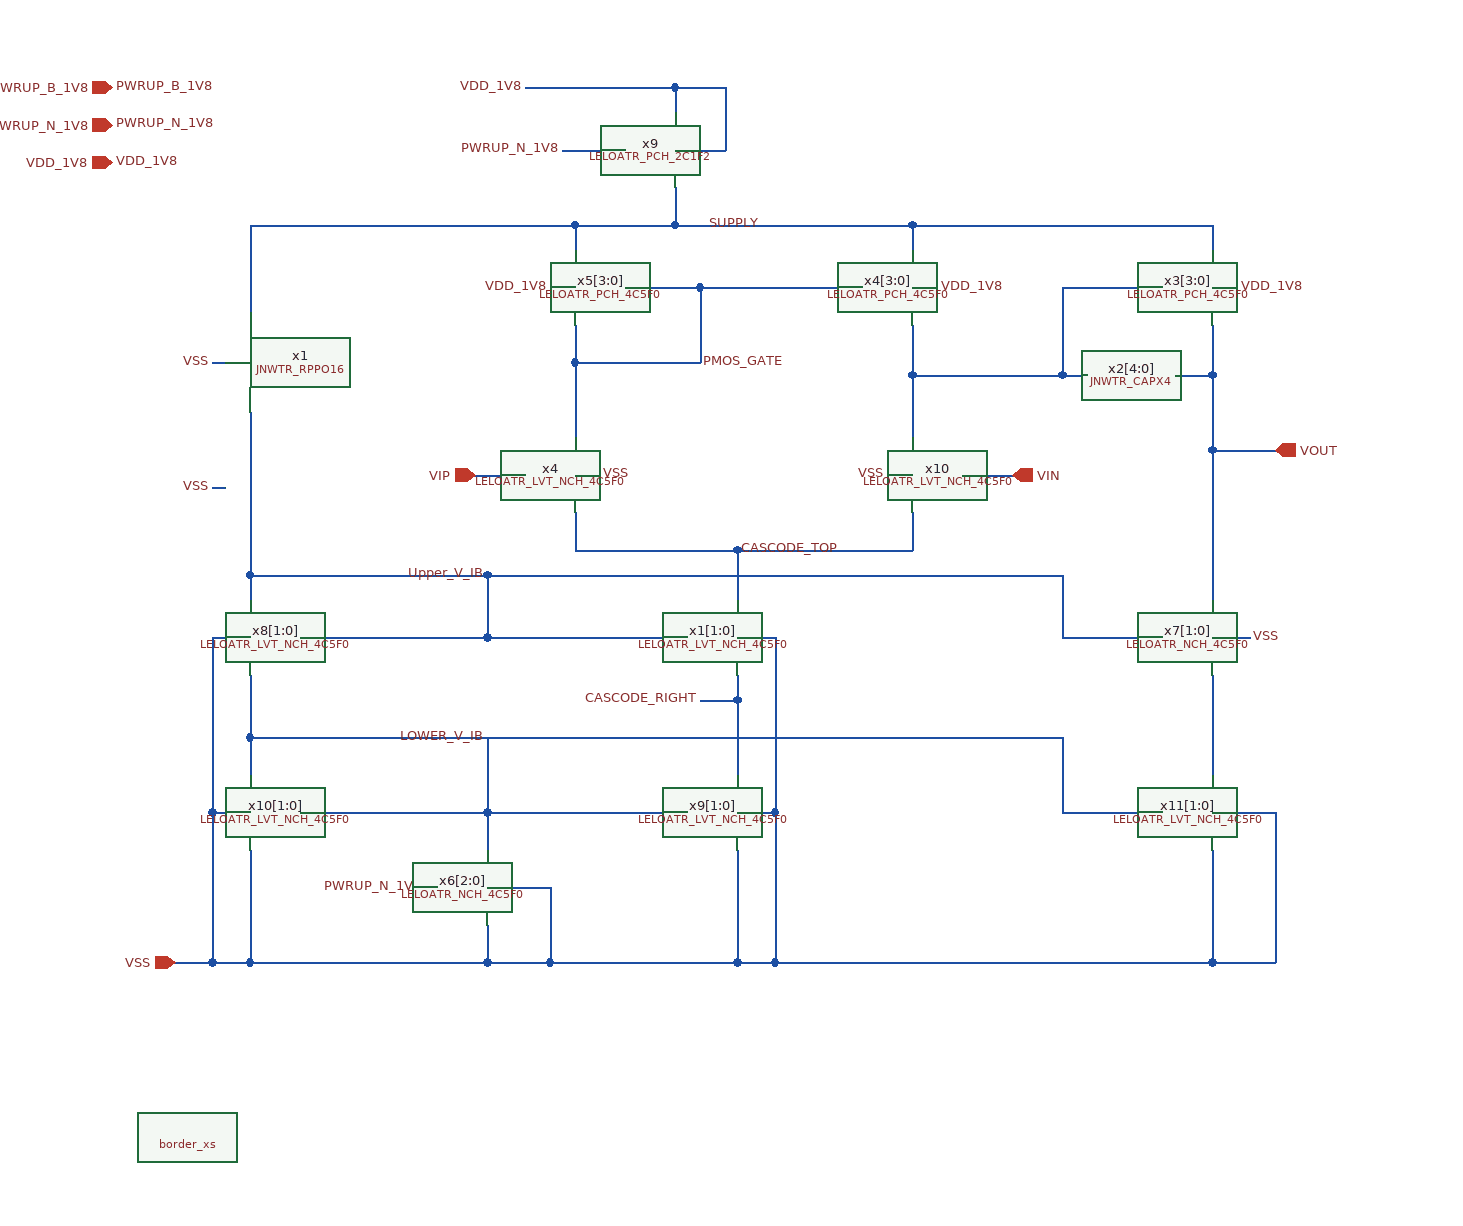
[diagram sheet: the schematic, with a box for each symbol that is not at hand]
v {xschem version=3.4.7 file_version=1.2}
G {}
K {}
V {}
S {}
E {}
N -510 -470 -450 -470 {lab=PMOS_GATE}
N -550 -410 -550 -350 {lab=PMOS_GATE}
N -280 -400 -280 -350 {lab=#net1}
N -550 -410 -450 -410 {lab=PMOS_GATE}
N -240 -320 -200 -320 {lab=VIN}
N -550 -290 -550 -260 {lab=CASCODE_TOP}
N -280 -290 -280 -260 {lab=CASCODE_TOP}
N -450 -470 -320 -470 {lab=PMOS_GATE}
N -450 -470 -450 -410 {lab=PMOS_GATE}
N -420 -260 -280 -260 {lab=CASCODE_TOP}
N -420 -260 -420 -220 {lab=CASCODE_TOP}
N -620 -190 -460 -190 {lab=Upper_V_IB}
N -840 -190 -810 -190 {lab=VSS}
N -420 -190 -390 -190 {lab=VSS}
N -280 -520 -280 -500 {lab=SUPPLY}
N -470 -520 -280 -520 {lab=SUPPLY}
N -550 -520 -550 -500 {lab=SUPPLY}
N -280 -470 -260 -470 {lab=VDD_1V8}
N -560 -580 -510 -580 {lab=PWRUP_N_1V8}
N -590 -630 -470 -630 {lab=VDD_1V8}
N -470 -630 -470 -610 {lab=VDD_1V8}
N -470 -550 -470 -520 {lab=SUPPLY}
N -470 -580 -430 -580 {lab=VDD_1V8}
N -430 -630 -430 -580 {lab=VDD_1V8}
N -470 -630 -430 -630 {lab=VDD_1V8}
N -420 70 -390 70 {lab=VSS}
N -570 -470 -550 -470 {lab=VDD_1V8}
N -810 -240 -620 -240 {lab=Upper_V_IB}
N -550 -320 -530 -320 {lab=VSS}
N -300 -320 -280 -320 {lab=VSS}
N -280 -520 -40 -520 {lab=SUPPLY}
N -40 -520 -40 -500 {lab=SUPPLY}
N -40 -470 -20 -470 {lab=VDD_1V8}
N -40 -190 -10 -190 {lab=VSS}
N -40 -340 10 -340 {lab=VOUT}
N -630 -320 -590 -320 {lab=VIP}
N -810 -270 -810 -240 {lab=Upper_V_IB}
N -810 -240 -810 -220 {lab=Upper_V_IB}
N -840 -310 -830 -310 {lab=VSS}
N -840 -410 -830 -410 {lab=VSS}
N -810 -370 -810 -350 {lab=Upper_V_IB}
N -810 -520 -550 -520 {lab=SUPPLY}
N -810 -520 -810 -450 {lab=SUPPLY}
N -40 -440 -40 -400 {lab=VOUT}
N -40 -340 -40 -220 {lab=VOUT}
N -620 40 -620 70 {lab=VSS}
N -390 -190 -390 -80 {lab=VSS}
N -390 70 -40 70 {lab=VSS}
N -160 -400 -140 -400 {lab=#net1}
N -70 -400 -40 -400 {lab=VOUT}
N -160 -470 -160 -400 {lab=#net1}
N -160 -470 -80 -470 {lab=#net1}
N -280 -400 -160 -400 {lab=#net1}
N -550 -260 -420 -260 {lab=CASCODE_TOP}
N -770 -190 -620 -190 {lab=Upper_V_IB}
N -620 -240 -620 -190 {lab=Upper_V_IB}
N -570 10 -570 70 {lab=VSS}
N -620 -50 -460 -50 {lab=LOWER_V_IB}
N -840 -50 -840 70 {lab=VSS}
N -390 -50 -390 70 {lab=VSS}
N -620 -50 -620 -20 {lab=LOWER_V_IB}
N -620 10 -570 10 {lab=VSS}
N -840 -50 -810 -50 {lab=VSS}
N -40 -50 -10 -50 {lab=VSS}
N -550 -440 -550 -410 {lab=PMOS_GATE}
N -570 70 -420 70 {lab=VSS}
N -550 -520 -470 -520 {lab=SUPPLY}
N -40 -400 -40 -340 {lab=VOUT}
N -810 70 -620 70 {lab=VSS}
N -840 70 -810 70 {lab=VSS}
N -870 70 -840 70 {lab=VSS}
N -280 -440 -280 -400 {lab=#net1}
N -620 70 -570 70 {lab=VSS}
N -810 -160 -810 -140 {lab=LOWER_V_IB}
N -770 -50 -620 -50 {lab=LOWER_V_IB}
N -840 -190 -840 -80 {lab=VSS}
N -40 -160 -40 -130 {lab=#net2}
N -420 -20 -420 70 {lab=VSS}
N -810 -20 -810 70 {lab=VSS}
N -810 -110 -810 -80 {lab=LOWER_V_IB}
N -420 -50 -390 -50 {lab=VSS}
N -40 70 10 70 {lab=VSS}
N 10 -50 10 70 {lab=VSS}
N -10 -50 10 -50 {lab=VSS}
N -810 -110 -740 -110 {lab=LOWER_V_IB}
N -160 -50 -80 -50 {lab=LOWER_V_IB}
N -160 -110 -160 -50 {lab=LOWER_V_IB}
N -160 -190 -80 -190 {lab=Upper_V_IB}
N -160 -240 -160 -190 {lab=Upper_V_IB}
N -620 -240 -160 -240 {lab=Upper_V_IB}
N -740 -110 -530 -110 {lab=LOWER_V_IB}
N -40 -100 -40 -80 {lab=#net2}
N -40 -20 -40 70 {lab=VSS}
N -810 -350 -810 -270 {lab=Upper_V_IB}
N -620 -110 -620 -50 {lab=LOWER_V_IB}
N -450 -140 -430 -140 {lab=CASCODE_RIGHT}
N -670 10 -660 10 {lab=PWRUP_N_1V8}
N -40 -130 -40 -100 {lab=#net2}
N -390 -80 -390 -50 {lab=VSS}
N -430 -140 -420 -140 {lab=CASCODE_RIGHT}
N -810 -140 -810 -110 {lab=LOWER_V_IB}
N -840 -80 -840 -50 {lab=VSS}
N -530 -110 -160 -110 {lab=LOWER_V_IB}
N -420 -160 -420 -140 {lab=CASCODE_RIGHT}
N -420 -140 -420 -80 {lab=CASCODE_RIGHT}
C {cborder/border_xs.sym} -860 210 0 0 {
user="Group 2"
company=""}
C {devices/ipin.sym} -870 70 0 0 {name=p2 lab=VSS}
C {devices/ipin.sym} -920 -600 0 0 {name=p3 lab=PWRUP_N_1V8}
C {devices/ipin.sym} -630 -320 0 0 {name=p4 lab=VIP}
C {devices/opin.sym} 10 -340 0 0 {name=p6 lab=VOUT}
C {devices/lab_wire.sym} -400 -520 0 0 {name=p7 sig_type=std_logic lab=SUPPLY}
C {devices/lab_wire.sym} -450 -410 2 0 {name=p8 sig_type=std_logic lab=PMOS_GATE}
C {devices/lab_pin.sym} -570 -470 0 0 {name=p9 sig_type=std_logic lab=VDD_1V8}
C {devices/lab_pin.sym} -260 -470 0 1 {name=p12 sig_type=std_logic lab=VDD_1V8}
C {devices/lab_wire.sym} -530 -320 0 1 {name=p13 sig_type=std_logic lab=VSS}
C {devices/lab_wire.sym} -300 -320 0 0 {name=p14 sig_type=std_logic lab=VSS}
C {devices/lab_pin.sym} -20 -470 0 1 {name=p15 sig_type=std_logic lab=VDD_1V8}
C {devices/lab_wire.sym} -620 -240 0 0 {name=p19 sig_type=std_logic lab=Upper_V_IB}
C {devices/ipin.sym} -200 -320 0 1 {name=p11 lab=VIN}
C {devices/lab_wire.sym} -840 -310 0 0 {name=p5 sig_type=std_logic lab=VSS}
C {devices/lab_wire.sym} -840 -410 0 0 {name=p17 sig_type=std_logic lab=VSS}
C {LELO_ATR_SKY130A/LELOATR_LVT_NCH_4C5F0.sym} -240 -320 0 1 {name=x10}
C {LELO_ATR_SKY130A/LELOATR_LVT_NCH_4C5F0.sym} -590 -320 0 0 {name=x4}
C {JNW_TR_SKY130A/JNWTR_CAPX4.sym} -80 -400 3 1 {name=x2[4:0]}
C {LELO_ATR_SKY130A/LELOATR_PCH_4C5F0.sym} -80 -470 0 0 {name=x3[3:0]}
C {devices/lab_wire.sym} -10 -190 0 1 {name=p16 sig_type=std_logic lab=VSS}
C {devices/ipin.sym} -920 -630 0 0 {name=p20 lab=PWRUP_B_1V8}
C {devices/lab_pin.sym} -920 -630 0 1 {name=p21 sig_type=std_logic lab=PWRUP_B_1V8}
C {LELO_ATR_SKY130A/LELOATR_LVT_NCH_4C5F0.sym} -460 -190 0 0 {name=x1[1:0]}
C {LELO_ATR_SKY130A/LELOATR_LVT_NCH_4C5F0.sym} -770 -190 0 1 {name=x8[1:0]}
C {LELO_ATR_SKY130A/LELOATR_NCH_4C5F0.sym} -80 -190 0 0 {name=x7[1:0]}
C {devices/lab_pin.sym} -920 -600 0 1 {name=p22 sig_type=std_logic lab=PWRUP_N_1V8}
C {devices/lab_pin.sym} -560 -580 0 0 {name=p23 sig_type=std_logic lab=PWRUP_N_1V8}
C {devices/lab_pin.sym} -670 10 0 0 {name=p24 sig_type=std_logic lab=PWRUP_N_1V8}
C {LELO_ATR_SKY130A/LELOATR_PCH_4C5F0.sym} -320 -470 0 0 {name=x4[3:0]}
C {LELO_ATR_SKY130A/LELOATR_PCH_4C5F0.sym} -510 -470 0 1 {name=x5[3:0]}
C {LELO_ATR_SKY130A/LELOATR_PCH_2C1F2.sym} -510 -580 0 0 {name=x9}
C {LELO_ATR_SKY130A/LELOATR_NCH_4C5F0.sym} -660 10 0 0 {name=x6[2:0]}
C {devices/ipin.sym} -920 -570 0 0 {name=p25 lab=VDD_1V8}
C {devices/lab_pin.sym} -920 -570 0 1 {name=p26 sig_type=std_logic lab=VDD_1V8}
C {devices/lab_pin.sym} -590 -630 0 0 {name=p1 sig_type=std_logic lab=VDD_1V8}
C {JNW_TR_SKY130A/JNWTR_RPPO16.sym} -810 -450 1 0 {name=x1 }
C {LELO_ATR_SKY130A/LELOATR_LVT_NCH_4C5F0.sym} -460 -50 0 0 {name=x9[1:0]}
C {LELO_ATR_SKY130A/LELOATR_LVT_NCH_4C5F0.sym} -770 -50 0 1 {name=x10[1:0]}
C {LELO_ATR_SKY130A/LELOATR_LVT_NCH_4C5F0.sym} -80 -50 0 0 {name=x11[1:0]}
C {devices/lab_wire.sym} -620 -110 0 0 {name=p10 sig_type=std_logic lab=LOWER_V_IB}
C {devices/lab_wire.sym} -420 -260 0 1 {name=p18 sig_type=std_logic lab=CASCODE_TOP}
C {devices/lab_wire.sym} -450 -140 0 0 {name=p28 sig_type=std_logic lab=CASCODE_RIGHT}
